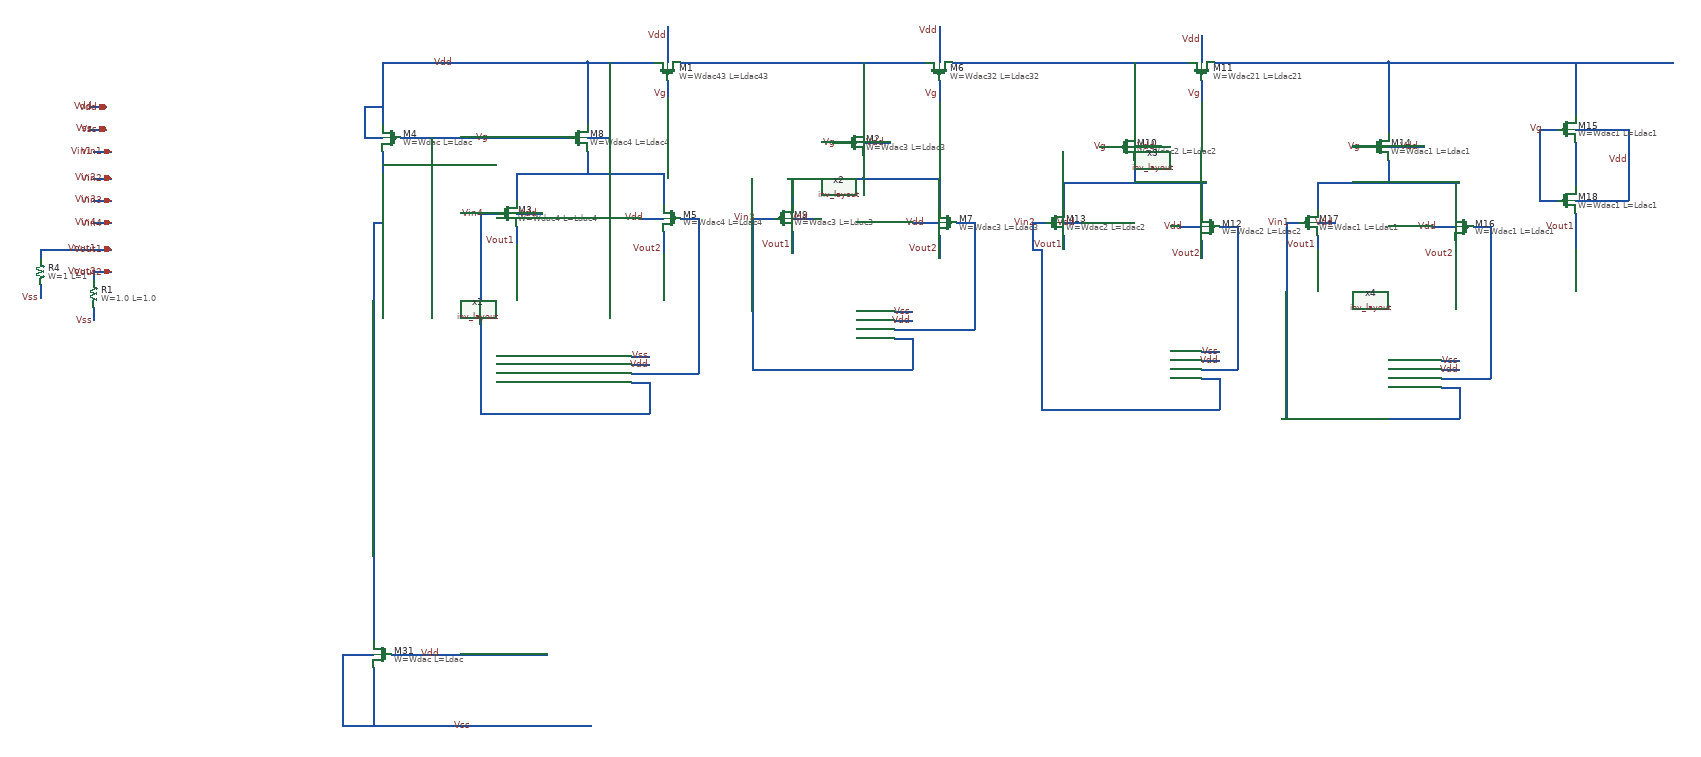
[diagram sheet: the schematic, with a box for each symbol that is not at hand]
v {xschem version=3.4.5 file_version=1.2
}
G {}
K {}
V {}
S {}
E {}
N -690 -170 -300 -170 {
lab=Vg}
N -430 30 -430 70 {
lab=Vout1}
N -510 0 -470 -0 {
lab=Vin4}
N -100 40 -100 90 {
lab=Vout2}
N -60 10 -20 10 {
lab=#net1}
N -270 -140 -270 -90 {
lab=#net2}
N -430 -90 -270 -90 {
lab=#net2}
N -430 -90 -430 -30 {
lab=#net2}
N -270 -90 -110 -90 {
lab=#net2}
N -110 -90 -100 -90 {
lab=#net2}
N -100 -90 -100 -20 {
lab=#net2}
N -730 -340 -730 -200 {
lab=Vdd}
N -730 -340 -280 -340 {
lab=Vdd}
N -280 -340 -270 -340 {
lab=Vdd}
N -270 -340 -270 -200 {
lab=Vdd}
N -270 -340 -120 -340 {
lab=Vdd}
N -730 -140 -730 -80 {
lab=Vg}
N -730 -110 -620 -110 {
lab=Vg}
N -620 -170 -620 -110 {
lab=Vg}
N -730 -90 -730 -30 {
lab=Vg}
N -90 -300 -90 -260 {
lab=Vg}
N 350 -130 350 -80 {
lab=#net3}
N 180 -80 350 -80 {
lab=#net3}
N 190 -80 190 -20 {
lab=#net3}
N 350 -80 510 -80 {
lab=#net3}
N 510 -80 520 -80 {
lab=#net3}
N 520 -80 520 -10 {
lab=#net3}
N 190 40 190 90 {
lab=Vout1}
N 520 50 520 100 {
lab=Vout2}
N 100 10 150 10 {
lab=Vin3}
N 560 20 600 20 {
lab=#net4}
N 730 20 760 20 {
lab=Vin2}
N 800 50 800 80 {
lab=Vout1}
N 1110 60 1110 100 {
lab=Vout2}
N 800 -70 800 -10 {
lab=#net5}
N 800 -70 960 -70 {
lab=#net5}
N 960 -120 960 -70 {
lab=#net5}
N 960 -70 1120 -70 {
lab=#net5}
N 280 -160 310 -160 {
lab=Vg}
N -60 -340 490 -340 {
lab=#net6}
N 1110 -70 1110 -0 {
lab=#net5}
N 520 -300 520 -250 {
lab=Vg}
N 550 -340 1080 -340 {
lab=#net7}
N 880 -150 920 -150 {
lab=Vg}
N 350 -340 350 -190 {
lab=#net6}
N 960 -340 960 -180 {
lab=#net7}
N -270 -170 -220 -170 {
lab=Vdd}
N -430 0 -370 0 {
lab=Vdd}
N -150 10 -100 10 {
lab=Vdd}
N -90 -420 -90 -340 {
lab=Vdd}
N 520 -420 520 -340 {
lab=Vdd}
N 1110 -400 1110 -340 {
lab=Vdd}
N 1300 20 1330 20 {
lab=Vin1}
N 1370 50 1370 80 {
lab=Vout1}
N 1680 60 1680 100 {
lab=Vout2}
N 1370 -70 1370 -10 {
lab=#net8}
N 1370 -70 1530 -70 {
lab=#net8}
N 1530 -120 1530 -70 {
lab=#net8}
N 1530 -70 1690 -70 {
lab=#net8}
N 1680 -70 1680 0 {
lab=#net8}
N 1450 -150 1490 -150 {
lab=Vg}
N 1530 -340 1530 -180 {
lab=#net9}
N 1140 -340 1530 -340 {
lab=#net9}
N 1530 -340 1650 -340 {
lab=#net9}
N 1720 30 1750 30 {
lab=#net10}
N 1150 30 1190 30 {
lab=#net11}
N 1650 -340 1710 -340 {
lab=#net9}
N -770 -170 -730 -170 {
lab=Vdd}
N 350 -160 410 -160 {
lab=Vdd}
N 960 -150 1020 -150 {
lab=Vdd}
N 1530 -150 1610 -150 {
lab=Vdd}
N 190 10 240 10 {
lab=Vdd}
N 460 20 520 20 {
lab=Vdd}
N 1370 20 1410 20 {
lab=Vdd}
N 1630 30 1680 30 {
lab=Vdd}
N 800 20 840 20 {
lab=Vdd}
N 1060 30 1110 30 {
lab=Vdd}
N -1390 -240 -1350 -240 {
lab=Vdd}
N -1390 -190 -1350 -190 {
lab=Vss}
N -1380 -140 -1340 -140 {
lab=Vin1}
N -1380 80 -1340 80 {
lab=Vout1}
N -1380 130 -1340 130 {
lab=Vout2}
N 1110 -300 1110 -250 {
lab=Vg}
N -770 -240 -770 -170 {
lab=Vdd}
N -770 -240 -730 -240 {
lab=Vdd}
N -220 -340 -220 -170 {
lab=Vdd}
N -1380 -80 -1340 -80 {
lab=Vin2}
N -1380 -30 -1340 -30 {
lab=Vin3}
N -1380 20 -1340 20 {
lab=Vin4}
N -20 10 -20 230 {
lab=#net1}
N -510 -0 -510 230 {
lab=Vin4}
N 100 10 100 220 {
lab=Vin3}
N 600 20 600 220 {
lab=#net4}
N 1300 20 1300 220 {
lab=Vin1}
N 1760 30 1760 220 {
lab=#net10}
N 1750 30 1760 30 {
lab=#net10}
N 1190 30 1190 230 {
lab=#net11}
N -1500 160 -1500 190 {
lab=Vss}
N -1500 90 -1500 100 {
lab=Vout1}
N -1500 80 -1500 90 {
lab=Vout1}
N -1500 80 -1370 80 {
lab=Vout1}
N -1380 210 -1380 240 {
lab=Vss}
N -1380 140 -1380 150 {
lab=Vout2}
N -1380 130 -1380 140 {
lab=Vout2}
N -510 230 -510 250 {
lab=Vin4}
N -20 230 -20 260 {
lab=#net1}
N 1190 230 1190 250 {
lab=#net11}
N 1300 220 1300 270 {
lab=Vin1}
N 1760 220 1760 260 {
lab=#net10}
N -750 1020 -750 1050 {
lab=Vss}
N -710 990 -680 990 {
lab=Vdd}
N -750 1050 -750 1150 {
lab=Vss}
N -710 1150 -260 1150 {
lab=Vss}
N -820 990 -750 990 {
lab=Vss}
N -820 990 -820 1150 {
lab=Vss}
N -820 1150 -700 1150 {
lab=Vss}
N -680 990 -360 990 {
lab=Vdd}
N -750 20 -750 770 {
lab=Vg}
N -750 20 -730 20 {
lab=Vg}
N -730 -30 -730 20 {
lab=Vg}
N -750 750 -750 960 {
lab=Vg}
N -170 320 -130 320 {
lab=Vss}
N -170 340 -130 340 {
lab=Vdd}
N -170 360 -130 360 {
lab=#net1}
N -170 380 -130 380 {
lab=Vin4}
N -130 360 -20 360 {
lab=#net1}
N -20 260 -20 360 {
lab=#net1}
N -130 380 -130 450 {
lab=Vin4}
N -510 450 -130 450 {
lab=Vin4}
N -510 230 -510 450 {
lab=Vin4}
N 420 220 460 220 {
lab=Vss}
N 420 240 460 240 {
lab=Vdd}
N 420 260 460 260 {
lab=#net4}
N 420 280 460 280 {
lab=Vin3}
N 460 280 460 350 {
lab=Vin3}
N 460 260 600 260 {
lab=#net4}
N 600 220 600 260 {
lab=#net4}
N 100 350 460 350 {
lab=Vin3}
N 100 210 100 350 {
lab=Vin3}
N 1110 310 1150 310 {
lab=Vss}
N 1110 330 1150 330 {
lab=Vdd}
N 1110 350 1150 350 {
lab=#net11}
N 1110 370 1150 370 {
lab=Vin2}
N 1150 370 1150 440 {
lab=Vin2}
N 1150 350 1190 350 {
lab=#net11}
N 1190 250 1190 350 {
lab=#net11}
N 750 230 750 440 {
lab=Vin2}
N 750 440 1150 440 {
lab=Vin2}
N 1650 330 1690 330 {
lab=Vss}
N 1650 350 1690 350 {
lab=Vdd}
N 1650 370 1690 370 {
lab=#net10}
N 1650 390 1690 390 {
lab=Vin1}
N 1690 390 1690 460 {
lab=Vin1}
N 1690 370 1760 370 {
lab=#net10}
N 1760 260 1760 370 {
lab=#net10}
N 1290 460 1690 460 {
lab=Vin1}
N 1300 270 1300 460 {
lab=Vin1}
N 1710 -340 2170 -340 {
lab=#net9}
N 1950 -340 1950 -220 {
lab=#net9}
N 1870 -190 1910 -190 {
lab=Vg}
N 1950 -160 1950 -100 {
lab=#net12}
N 1950 -100 1950 -60 {
lab=#net12}
N 1950 -190 2070 -190 {
lab=Vdd}
N 2070 -190 2070 -30 {
lab=Vdd}
N 1950 -30 2070 -30 {
lab=Vdd}
N 1870 -30 1910 -30 {
lab=Vg}
N 1870 -190 1870 -30 {
lab=Vg}
N 1950 -0 1950 80 {
lab=Vout1}
N 750 80 750 230 {
lab=Vin2}
N 730 80 750 80 {
lab=Vin2}
N 730 20 730 80 {
lab=Vin2}
C {sky130_fd_pr/pfet_01v8.sym} -290 -170 0 0 {name=M8
L=Ldac4
W=Wdac4
nf=1 mult=1
model=pfet_01v8
spiceprefix=X
}
C {sky130_fd_pr/pfet_01v8.sym} -90 -320 3 0 {name=M1
L=Ldac43
W=Wdac43
nf=1 mult=1
model=pfet_01v8
spiceprefix=X
}
C {sky130_fd_pr/pfet_01v8.sym} -710 -170 0 1 {name=M4
L=Ldac
W=Wdac
nf=1 mult=1
model=pfet_01v8
spiceprefix=X
}
C {sky130_fd_pr/pfet_01v8.sym} -80 10 0 1 {name=M5
L=Ldac4
W=Wdac4
nf=1 mult=1
model=pfet_01v8
spiceprefix=X
}
C {sky130_fd_pr/pfet_01v8.sym} -450 0 0 0 {name=M3
L=Ldac4
W=Wdac4
nf=1 mult=1
model=pfet_01v8
spiceprefix=X
}
C {sky130_fd_pr/pfet_01v8.sym} 330 -160 0 0 {name=M2
L=Ldac3
W=Wdac3
nf=1 mult=1
model=pfet_01v8
spiceprefix=X
}
C {sky130_fd_pr/pfet_01v8.sym} 520 -320 3 0 {name=M6
L=Ldac32
W=Wdac32
nf=1 mult=1
model=pfet_01v8
spiceprefix=X
}
C {sky130_fd_pr/pfet_01v8.sym} 540 20 0 1 {name=M7
L=Ldac3
W=Wdac3
nf=1 mult=1
model=pfet_01v8
spiceprefix=X
}
C {sky130_fd_pr/pfet_01v8.sym} 170 10 0 0 {name=M9
L=Ldac3
W=Wdac3
nf=1 mult=1
model=pfet_01v8
spiceprefix=X
}
C {sky130_fd_pr/pfet_01v8.sym} 940 -150 0 0 {name=M10
L=Ldac2
W=Wdac2
nf=1 mult=1
model=pfet_01v8
spiceprefix=X
}
C {sky130_fd_pr/pfet_01v8.sym} 1110 -320 3 0 {name=M11
L=Ldac21
W=Wdac21
nf=1 mult=1
model=pfet_01v8
spiceprefix=X
}
C {sky130_fd_pr/pfet_01v8.sym} 1130 30 0 1 {name=M12
L=Ldac2
W=Wdac2
nf=1 mult=1
model=pfet_01v8
spiceprefix=X
}
C {sky130_fd_pr/pfet_01v8.sym} 780 20 0 0 {name=M13
L=Ldac2
W=Wdac2
nf=1 mult=1
model=pfet_01v8
spiceprefix=X
}
C {sky130_fd_pr/pfet_01v8.sym} 1510 -150 0 0 {name=M14
L=Ldac1
W=Wdac1
nf=1 mult=1
model=pfet_01v8
spiceprefix=X
}
C {sky130_fd_pr/pfet_01v8.sym} 1700 30 0 1 {name=M16
L=Ldac1
W=Wdac1
nf=1 mult=1
model=pfet_01v8
spiceprefix=X
}
C {sky130_fd_pr/pfet_01v8.sym} 1350 20 0 0 {name=M17
L=Ldac1
W=Wdac1
nf=1 mult=1
model=pfet_01v8
spiceprefix=X
}
C {devices/iopin.sym} -1350 -240 0 0 {name=p1 lab=Vdd




}
C {devices/iopin.sym} -1350 -190 0 0 {name=p2 lab=Vss




}
C {devices/lab_wire.sym} -1380 -190 0 0 {name=p9 sig_type=std_logic lab=Vss}
C {devices/lab_wire.sym} -1380 -240 0 0 {name=p6 sig_type=std_logic lab=Vdd
}
C {devices/iopin.sym} -1340 -140 0 0 {name=p7 lab=Vin1





}
C {devices/lab_wire.sym} -1380 -140 0 0 {name=p8 sig_type=std_logic lab=Vin1

}
C {devices/iopin.sym} -1340 80 0 0 {name=p10 lab=Vout1



}
C {devices/lab_wire.sym} -1370 80 0 0 {name=p11 sig_type=std_logic lab=Vout1
}
C {devices/iopin.sym} -1340 130 0 0 {name=p12 lab=Vout2




}
C {devices/lab_wire.sym} -1370 130 0 0 {name=p13 sig_type=std_logic lab=Vout2
}
C {devices/lab_wire.sym} -570 -340 0 0 {name=p16 sig_type=std_logic lab=Vdd
}
C {devices/lab_wire.sym} -490 -170 0 0 {name=p17 sig_type=std_logic lab=Vg

}
C {devices/lab_wire.sym} -90 -270 0 0 {name=p20 sig_type=std_logic lab=Vg

}
C {devices/lab_wire.sym} 290 -160 0 0 {name=p21 sig_type=std_logic lab=Vg

}
C {devices/lab_wire.sym} 520 -270 0 0 {name=p22 sig_type=std_logic lab=Vg

}
C {devices/lab_wire.sym} 900 -150 0 0 {name=p23 sig_type=std_logic lab=Vg

}
C {devices/lab_wire.sym} 1470 -150 0 0 {name=p24 sig_type=std_logic lab=Vg

}
C {devices/lab_wire.sym} -380 0 0 0 {name=p26 sig_type=std_logic lab=Vdd
}
C {devices/lab_wire.sym} -140 10 0 0 {name=p27 sig_type=std_logic lab=Vdd
}
C {devices/lab_wire.sym} 230 10 0 0 {name=p28 sig_type=std_logic lab=Vdd
}
C {devices/lab_wire.sym} 490 20 0 0 {name=p29 sig_type=std_logic lab=Vdd
}
C {devices/lab_wire.sym} 830 20 0 0 {name=p30 sig_type=std_logic lab=Vdd
}
C {devices/lab_wire.sym} 1070 30 0 0 {name=p31 sig_type=std_logic lab=Vdd
}
C {devices/lab_wire.sym} 1410 20 0 0 {name=p32 sig_type=std_logic lab=Vdd
}
C {devices/lab_wire.sym} 1640 30 0 0 {name=p33 sig_type=std_logic lab=Vdd
}
C {devices/lab_wire.sym} 400 -160 0 0 {name=p36 sig_type=std_logic lab=Vdd
}
C {devices/lab_wire.sym} 1010 -150 0 0 {name=p37 sig_type=std_logic lab=Vdd
}
C {devices/lab_wire.sym} 1600 -150 0 0 {name=p38 sig_type=std_logic lab=Vdd
}
C {devices/iopin.sym} -1340 -80 0 0 {name=p40 lab=Vin2






}
C {devices/lab_wire.sym} -1370 -80 0 0 {name=p41 sig_type=std_logic lab=Vin2



}
C {devices/iopin.sym} -1340 -30 0 0 {name=p42 lab=Vin3





}
C {devices/lab_wire.sym} -1370 -30 0 0 {name=p43 sig_type=std_logic lab=Vin3

}
C {devices/iopin.sym} -1340 20 0 0 {name=p44 lab=Vin4





}
C {devices/lab_wire.sym} -1370 20 0 0 {name=p45 sig_type=std_logic lab=Vin4

}
C {devices/lab_wire.sym} -500 0 0 0 {name=p46 sig_type=std_logic lab=Vin4

}
C {devices/lab_wire.sym} 110 10 0 0 {name=p47 sig_type=std_logic lab=Vin3

}
C {devices/lab_wire.sym} 740 20 0 0 {name=p48 sig_type=std_logic lab=Vin2



}
C {devices/lab_wire.sym} 1310 20 0 0 {name=p49 sig_type=std_logic lab=Vin1

}
C {devices/lab_wire.sym} -430 60 0 0 {name=p14 sig_type=std_logic lab=Vout1
}
C {devices/lab_wire.sym} 190 70 0 0 {name=p15 sig_type=std_logic lab=Vout1
}
C {devices/lab_wire.sym} 800 70 0 0 {name=p18 sig_type=std_logic lab=Vout1
}
C {devices/lab_wire.sym} 1370 70 0 0 {name=p19 sig_type=std_logic lab=Vout1
}
C {devices/lab_wire.sym} -100 80 0 0 {name=p52 sig_type=std_logic lab=Vout2
}
C {devices/lab_wire.sym} 520 80 0 0 {name=p53 sig_type=std_logic lab=Vout2
}
C {devices/lab_wire.sym} 1110 90 0 0 {name=p54 sig_type=std_logic lab=Vout2
}
C {devices/lab_wire.sym} 1680 90 0 0 {name=p55 sig_type=std_logic lab=Vout2
}
C {devices/lab_wire.sym} 1110 -270 0 0 {name=p57 sig_type=std_logic lab=Vg

}
C {devices/lab_wire.sym} -90 -400 0 0 {name=p58 sig_type=std_logic lab=Vdd
}
C {devices/lab_wire.sym} 520 -410 0 0 {name=p59 sig_type=std_logic lab=Vdd
}
C {devices/lab_wire.sym} 1110 -390 0 0 {name=p60 sig_type=std_logic lab=Vdd
}
C {devices/lab_pin.sym} -1500 190 0 0 {name=p3 sig_type=std_logic lab=Vss
}
C {devices/lab_pin.sym} -1380 240 0 0 {name=p5 sig_type=std_logic lab=Vss
}
C {sky130_fd_pr/res_generic_po.sym} -1500 130 0 0 {name=R4
W=1
L=1
model=res_generic_po
spiceprefix=X
 mult=0.01}
C {sky130_fd_pr/res_generic_po.sym} -1380 180 0 0 {name=R1
W=1.0
L=1.0
model=res_generic_po
spiceprefix=X
 mult=0.01}
C {sky130_fd_pr/nfet_01v8.sym} -730 990 0 1 {name=M31
L=Ldac
W=Wdac
nf=1 mult=1
model=nfet_01v8
spiceprefix=X
}
C {devices/lab_wire.sym} -530 1150 0 0 {name=p74 sig_type=std_logic lab=Vss}
C {devices/lab_wire.sym} -600 990 0 0 {name=p4 sig_type=std_logic lab=Vdd
}
C {/home/eserlis/inv_layout.sym} -320 350 0 0 {name=x1}
C {devices/lab_wire.sym} -130 320 0 0 {name=p69 sig_type=std_logic lab=Vss
}
C {devices/lab_wire.sym} -130 340 0 0 {name=p70 sig_type=std_logic lab=Vdd
}
C {/home/eserlis/inv_layout.sym} 270 250 0 0 {name=x2}
C {devices/lab_wire.sym} 460 220 0 0 {name=p61 sig_type=std_logic lab=Vss
}
C {devices/lab_wire.sym} 460 240 0 0 {name=p62 sig_type=std_logic lab=Vdd
}
C {/home/eserlis/inv_layout.sym} 960 340 0 0 {name=x3}
C {devices/lab_wire.sym} 1150 310 0 0 {name=p63 sig_type=std_logic lab=Vss
}
C {devices/lab_wire.sym} 1150 330 0 0 {name=p64 sig_type=std_logic lab=Vdd
}
C {/home/eserlis/inv_layout.sym} 1500 360 0 0 {name=x4}
C {devices/lab_wire.sym} 1690 330 0 0 {name=p65 sig_type=std_logic lab=Vss
}
C {devices/lab_wire.sym} 1690 350 0 0 {name=p66 sig_type=std_logic lab=Vdd
}
C {sky130_fd_pr/pfet_01v8.sym} 1930 -190 0 0 {name=M15
L=Ldac1
W=Wdac1
nf=1 mult=1
model=pfet_01v8
spiceprefix=X
}
C {sky130_fd_pr/pfet_01v8.sym} 1930 -30 0 0 {name=M18
L=Ldac1
W=Wdac1
nf=1 mult=1
model=pfet_01v8
spiceprefix=X
}
C {devices/lab_wire.sym} 1880 -190 0 0 {name=p25 sig_type=std_logic lab=Vg

}
C {devices/lab_wire.sym} 2070 -120 0 0 {name=p34 sig_type=std_logic lab=Vdd
}
C {devices/lab_wire.sym} 1950 30 0 0 {name=p35 sig_type=std_logic lab=Vout1
}
